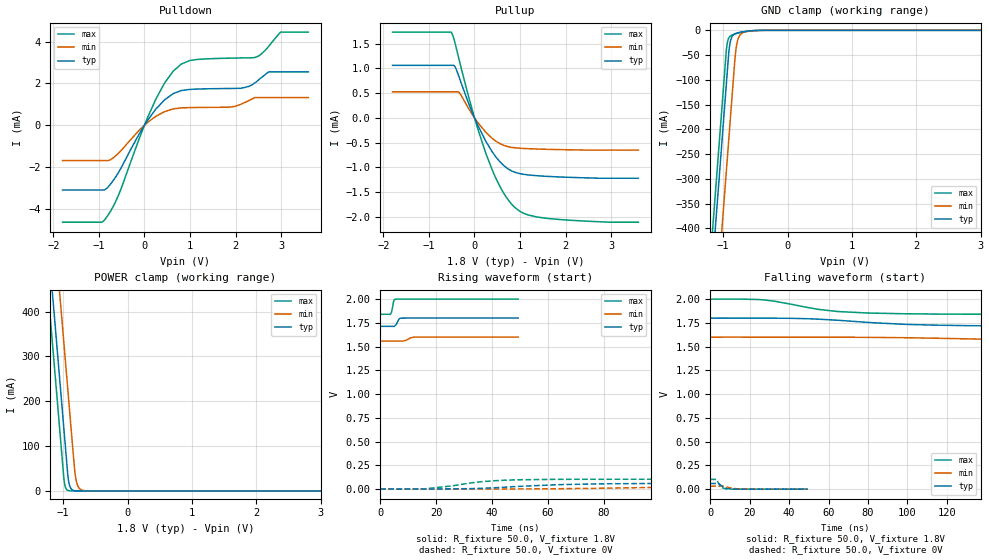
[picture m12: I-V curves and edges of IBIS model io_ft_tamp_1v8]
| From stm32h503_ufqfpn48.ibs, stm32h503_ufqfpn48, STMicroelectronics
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[Model]   io_ft_tamp_1v8
Model_type I/O
Polarity   Non-Inverting
Enable   Active-Low
| CAP_THRESHOLD on pad IOFT is "UDTCAPC" :
| Rising=20.0% of vddios   Falling=80.0% of vddios
| C_comp min and max val. don't necessarily correlate with the min and max pvt
| but are the smallest and greatest pad capacitance found.
| var   typ   min   max
C_comp   2.49737pF  2.47540pF  2.56125pF
|C_comp_pullup   1.39005pF  1.35310pF  1.33705pF
|C_comp_pulldown   1.10732pF  1.12230pF  1.22420pF
Vinl = 480.0mV
Vinh = 1.4V
Vmeas = 900.0mV   | Reference voltage for timing measurements
Cref  = 50.0pF   | Timing specification test load capacitance value
Rref  = 100.0MOhm   | Timing specification test load resistance value
Vref  = 900.0mV   | Timing specification test load voltage
[Model Spec]
| TIME_THRESHOLD on pin ZIV11 is "CMOS" :
| Rising=40.0% of vdd   Falling=60.0% of vdd
Vinl 703.80000mV 631.80000mV 784.80000mV
Vinh 1.06220V 937.20000mV 1.16620V
| variable   typ   min   max
[Temperature Range] 25.0 125.0 -40.0
| variable   typ   min   max
[Voltage Range] 1.8V 1.6V 2.0V
| variable   typ   min   max
[POWER Clamp Reference] 1.8V 1.6V 2.0V
| variable   typ   min   max
[GND Clamp Reference] 0V 0V 0V
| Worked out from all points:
|   slope of the pulldown table from 0 to 0.27 V, typ, clamps not added: 331 ohm
|   slope of the pullup table from 0 to 0.27 V, typ, clamps not added: 534 ohm
|   GND clamp passes 1 mA (typ) near -0.57 V on its own axis
|   POWER clamp passes 1 mA (typ) near -0.84 V on its own axis
|   rising waveform, R_fixture 50.0, V_fixture 1.8V: 20-80 % time 951ps typ, NA min, 625ps max; typ from 1.71 V to 1.8 V
|   falling waveform, R_fixture 50.0, V_fixture 1.8V: 20-80 % time 46.6ns typ, NA min, 28.4ns max; typ from 1.8 V to 1.71 V
|   rising waveform, R_fixture 50.0, V_fixture 0V: 20-80 % time 27.2ns typ, NA min, 16.9ns max; typ from 0 V to 0.059 V
|   falling waveform, R_fixture 50.0, V_fixture 0V: 20-80 % time 2.81ns typ, NA min, 1.93ns max; typ from 0.059 V to 0 V
[POWER Clamp]
-1.8V     1.518A     1.709A     1.407A
-1.24V    565.8mA    757.2mA    454.5mA
-1.18V    463.8mA    655.2mA    352.5mA
-1.12V    361.8mA    553.2mA    250.5mA
-1.05V    242.8mA    434.2mA    131.5mA
-980mV    123.8mA    315.2mA    17.95mA
-930mV    38.81mA    230.2mA    1.49mA
-890mV    8.18mA     162.2mA    203.5uA
-810mV    363.5uA    33.6mA     3.797uA
-770mV    76.62uA    10.47mA    518.7nA
-710mV    7.415uA    1.822mA    26.22nA
3.6V      0A         0A         0A
[GND Clamp]
-1.8V     -1.553A    -1.729A    -1.484A
-1.24V    -601mA     -776.8mA   -532mA
-1.05V    -278mA     -453.8mA   -209mA
-960mV    -125mA     -300.8mA   -55.98mA
-950mV    -108mA     -283.8mA   -39.16mA
-910mV    -41.67mA   -215.8mA   -14.99mA
-870mV    -15.03mA   -147.8mA   -10.01mA
-820mV    -7.38mA    -62.82mA   -7.426mA
-790mV    -5.729mA   -29.16mA   -6.271mA
-740mV    -4.051mA   -9.807mA   -4.645mA
-660mV    -2.296mA   -3.153mA   -2.565mA
3.6V      1.737nA    305nA      113.6pA
| variable   typ   min   max
[Pullup Reference] 1.8V 1.6V 2.0V
| variable   typ   min   max
[Pulldown Reference] 0V 0V 0V
[Pullup]
-1.8V     1.062mA    527.1uA    1.734mA
-500mV    1.062mA    527.1uA    1.716mA
-430mV    1.034mA    527.1uA    1.52mA
-330mV    802.6uA    503.1uA    1.148mA
0V        7.509pA    697pA      4.404pA
250mV     -475.1uA   -292.7uA   -718uA
570mV     -897.4uA   -525.5uA   -1.405mA
750mV     -1.038mA   -585.1uA   -1.67mA
900mV     -1.103mA   -606.1uA   -1.821mA
1.18V     -1.153mA   -623uA     -1.963mA
1.56V     -1.181mA   -635uA     -2.028mA
3.6V      -1.22mA    -651uA     -2.109mA
[Pulldown]
-1.8V     -3.103mA   -1.698mA   -4.646mA
-940mV    -3.103mA   -1.698mA   -4.646mA
-850mV    -3.062mA   -1.698mA   -4.458mA
-570mV    -2.26mA    -1.338mA   -3.345mA
250mV     768.4uA    423.6uA    1.247mA
630mV     1.508mA    776.9uA    2.582mA
810mV     1.658mA    825.5uA    2.926mA
1.93V     1.756mA    876.2uA    3.208mA
2.43V     2.031mA    1.32mA     3.244mA
2.73V     2.551mA    1.32mA     3.779mA
2.99V     2.551mA    1.32mA     4.454mA
3.6V      2.551mA    1.32mA     4.454mA
[Ramp]
dV/dt_r 35.6819mV/26.60942ns 19.04344mV/51.07122ns 61.70407mV/15.6559ns
dV/dt_f 52.53437mV/45.46749ns 25.57776mV/80.09823ns 96.13693mV/28.098ns
R_load = 50.0
| Removed startup time: 0s 0s 0s  .
| Removed end time: 49.4ns.
[Rising Waveform]
R_fixture   = 50.0
V_fixture   = 1.8V
V_fixture_min = 1.6V
V_fixture_max = 2.0V
0s        1.712V     1.557V     1.84V
3.65ns    1.712V     1.557V     1.841V
4.15ns    1.712V     1.557V     1.877V
4.85ns    1.712V     1.557V     1.982V
5.1ns     1.715V     1.557V     1.995V
5.45ns    1.724V     1.557V     1.999V
6.8ns     1.791V     1.557V     2V
7.85ns    1.8V       1.557V     2V
12.1ns    1.8V       1.599V     2V
49.4ns    1.8V       1.6V       2V
| Removed startup time: 0s 0s 0s  .
| Removed end time: 799.4ns.
[Falling Waveform]
R_fixture   = 50.0
V_fixture   = 1.8V
V_fixture_min = 1.6V
V_fixture_max = 2.0V
0s        1.8V       1.6V       2V
27.4ns    1.8V       1.6V       1.992V
32.65ns   1.8V       1.6V       1.978V
54.5ns    1.79V      1.6V       1.893V
65.25ns   1.777V     1.599V     1.869V
81.6ns    1.753V     1.598V     1.853V
112.4ns   1.727V     1.59V      1.844V
163.2ns   1.716V     1.571V     1.84V
244.8ns   1.713V     1.561V     1.84V
799.4ns   1.712V     1.557V     1.84V
| Removed startup time: 0s 0s 0s  .
| Removed end time: 799.3ns.
[Rising Waveform]
R_fixture   = 50.0
V_fixture   = 0V
V_fixture_min = 0V
V_fixture_max = 0V
0s        59.38nV    365.4nV    54.55nV
16.4ns    -52.96uV   -42.68uV   3.318mV
25.7ns    1.404mV    -21.13uV   32.93mV
37.3ns    8.654mV    145.4uV    79.4mV
48.9ns    26.13mV    872.3uV    96.47mV
62.8ns    44.34mV    2.877mV    101.5mV
95.8ns    57.84mV    15.64mV    102.7mV
130.5ns   59.26mV    26.44mV    102.8mV
179.5ns   59.41mV    30.85mV    102.8mV
799.3ns   59.47mV    31.74mV    102.8mV
| Removed startup time: 0s 0s 0s  .
| Removed end time: 49.4ns.
[Falling Waveform]
R_fixture   = 50.0
V_fixture   = 0V
V_fixture_min = 0V
V_fixture_max = 0V
0s        59.48mV    31.76mV    102.8mV
3.1ns     59.45mV    31.77mV    103.5mV
4.1ns     59.96mV    31.73mV    66.77mV
4.9ns     47.63mV    31.75mV    39.01mV
5.5ns     38.2mV     31.73mV    22.97mV
7.05ns    18.03mV    28.89mV    8.297mV
8.4ns     7.869mV    21.79mV    1.113mV
13.1ns    256.4uV    5.085mV    123uV
18.15ns   79.59uV    756.6uV    57.55uV
49.4ns    24.67uV    11.49uV    25.58uV
